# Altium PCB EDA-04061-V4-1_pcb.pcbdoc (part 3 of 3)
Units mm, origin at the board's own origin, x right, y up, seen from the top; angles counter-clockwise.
Board outline 105 x 56 mm, 6 copper layers (Top Layer, L2, L3, L4, L5, Bottom Layer), stack 1.58 mm thick; 213 components, 137 nets, 766 pads, 477 vias.

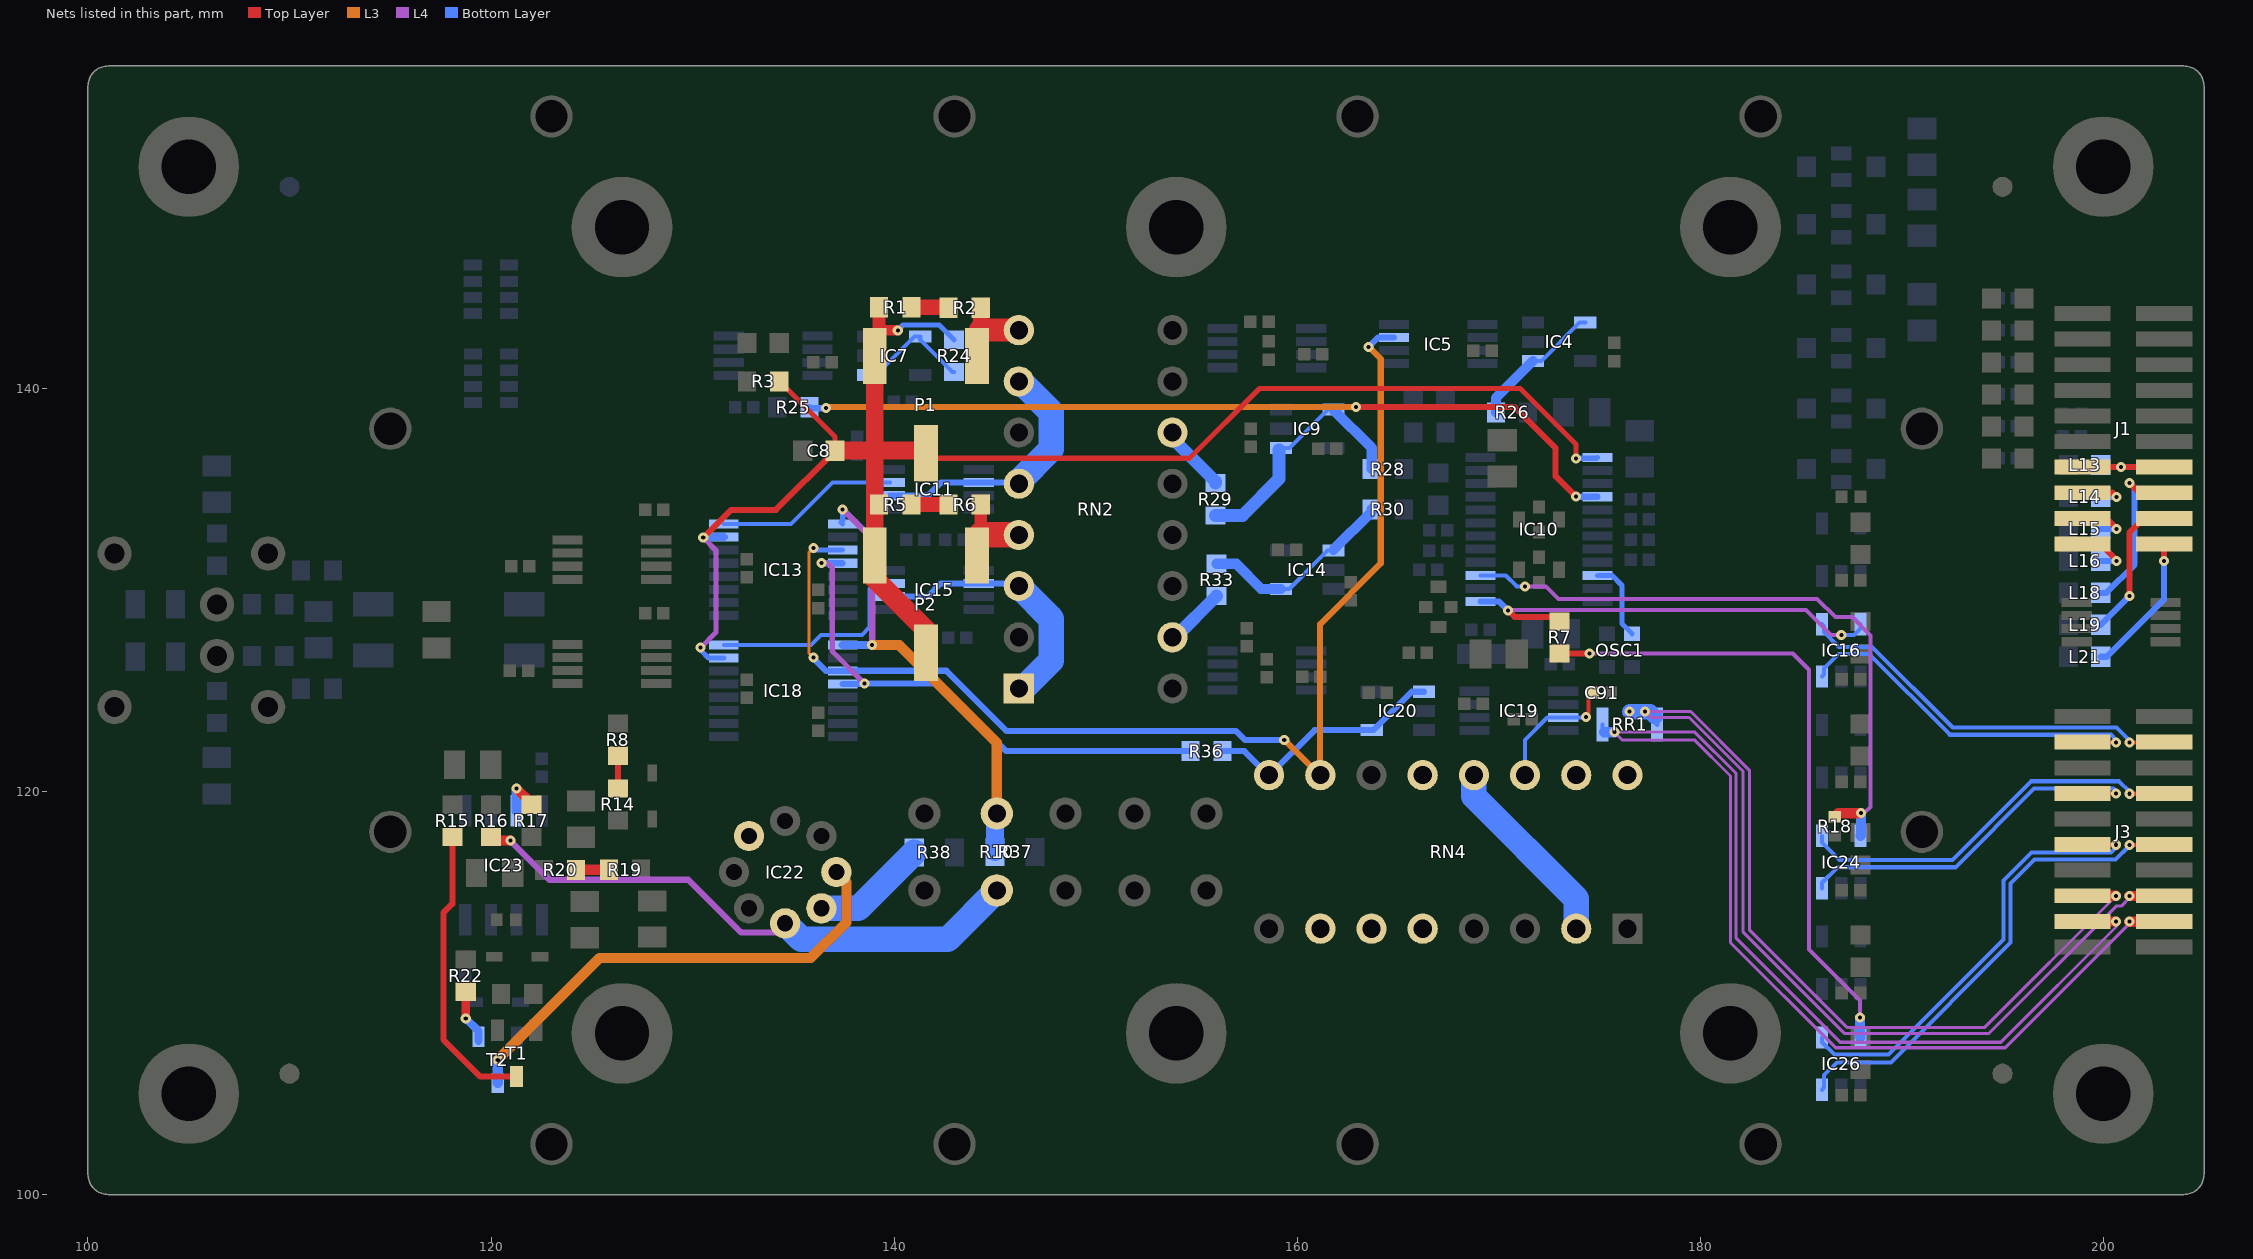
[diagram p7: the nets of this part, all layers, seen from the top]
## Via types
v1: diameter 0.5, hole 0.2, Top Layer to Bottom Layer, tented both sides, 477 vias

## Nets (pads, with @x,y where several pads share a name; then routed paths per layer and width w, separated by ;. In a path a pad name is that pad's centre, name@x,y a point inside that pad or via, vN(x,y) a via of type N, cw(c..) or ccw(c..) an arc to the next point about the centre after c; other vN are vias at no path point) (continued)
NetIC4_1: IC4.1 IC4.4 R26.1 | length 6.7
  Bottom Layer w0.203: IC4.1@171.7,141.363 172.122,141.363 174.022,143.263 IC4.4@174.3,143.263
  Bottom Layer w0.508: R26.1@169.863,138.808 169.863,139.526 IC4.1@171.7,141.363
NetIC7_1: IC7.1 IC7.4 R24.1 | length 5.9
  Bottom Layer w0.203: IC7.1@138.7,140.669 139.112,140.669 141.012,142.569 IC7.4@141.3,142.569 141.3,142.401 142.888,140.813 R24.1@142.977,140.813
NetIC9_1: IC9.1 IC9.4 R28.1 R29.2 | length 12.6
  Bottom Layer w0.203: IC9.1@159.2,137.05 159.623,137.05 161.523,138.95 IC9.4@161.8,138.95
  Bottom Layer w0.254: IC9.1@159.106,136.956 IC9.1@159.2,137.05
  Bottom Layer w0.508: IC9.4@161.8,138.95 163.7,137.05 R28.1@163.7,136
  Bottom Layer w0.635: R29.2@155.946,133.7 157.289,133.7 159.106,135.517 IC9.1@159.106,136.956
NetIC10_10: IC10.10 OSC1.3 | length 4
  Bottom Layer w0.254: IC10.10@174.9,130.725 175.62,130.725 176.124,130.221 176.124,128.326 OSC1.3@176.625,127.825
NetIC11_2: IC11.2 IC11.6 RN2.5 RN2.7 | length 13.1
  Bottom Layer w0.305: IC11.2@139.8,134.675 141.675,134.675 142.325,135.325 IC11.6@144.2,135.325 RN2.5@146.135,135.325
  Bottom Layer w1.27: RN2.5@146.19,135.27 146.135,135.325 147.803,136.993 147.803,138.819 146.272,140.35 RN2.7@146.19,140.35
NetIC11_3: IC11.3 IC13.8 | length 9.1
  Bottom Layer w0.203: IC13.8@131.547,133.276 134.894,133.276 136.943,135.325 IC11.3@139.8,135.325
NetIC14_1: IC14.1 IC14.4 R30.1 R33.2 | length 9.9
  Bottom Layer w0.203: IC14.4@159.2,130.05 159.608,130.05 161.508,131.95 IC14.1@161.8,131.95 IC14.1@161.8,131.988
  Bottom Layer w0.508: R33.2@156,131.3 156.973,131.3 158.223,130.05 IC14.4@159.2,130.05 ; IC14.1@161.8,131.988 163.7,133.888 R30.1@163.7,134
NetIC15_2: IC15.2 IC15.6 RN2.1 RN2.3 | length 13.3
  Bottom Layer w0.203: RN2.3@146.055,130.325 RN2.3@146.19,130.19
  Bottom Layer w0.305: IC15.2@139.8,129.675 141.675,129.675 142.325,130.325 IC15.6@144.2,130.325 RN2.3@146.055,130.325
  Bottom Layer w1.27: RN2.1@146.19,125.11 146.413,125.11 147.803,126.5 147.803,128.577 RN2.3@146.19,130.19
NetIC15_3: IC15.3 IC18.8 | length 10.6
  Bottom Layer w0.203: IC18.8@131.55,127.275 135.878,127.275 136.373,127.77 138.405,127.77 138.786,128.151 138.786,130.056 139.055,130.325 IC15.3@139.8,130.325
NetIC20_1: IC20.1 IC20.4 R36.1 RN4.9 | length 12.2
  Bottom Layer w0.305: R36.1@156.3,122 157.383,122 158.598,120.785 160.863,123.05 IC20.4@163.7,123.05 163.784,123.05 165.684,124.95 IC20.1@166.3,124.95
NetIC22_2: IC22.2 T2.3 | length 24
  L3 w0.508: v1(120.332,106.68) 125.395,111.743 135.871,111.743 137.643,113.515 137.643,115.492 IC22.2@137.135,116
  Bottom Layer w0.508: T2.3@120.332,105.53 v1(120.332,106.68)
NetIC22_3: IC22.3 R38.1 | length 5.8
  Bottom Layer w1.27: IC22.3@136.391,114.204 138.229,114.204 R38.1@141,116.975
NetIC22_4: IC22.4 R10.2 R16.1 | length 28.6
  Top Layer w0.508: R16.1@120,117.74 120.177,117.563 v1(120.956,117.563)
  L4 w0.152: IC22.4@134.135,113 IC22.4@134.595,113.46
  L4 w0.305: v1(120.956,117.563) 122.9,115.619 129.785,115.619 132.404,113 IC22.4@134.135,113
  Bottom Layer w1.27: IC22.4@134.595,113.46 135.388,112.667 142.67,112.667 R10.2@145.097,115.094 R10.2@145.097,115.05
NetIC23_3: IC23.3 R17.2 | length 2.2
  Top Layer w0.508: v1(121.26,120.15) 122,119.41 R17.2@122,119.34
  Bottom Layer w0.508: IC23.3@121.26,119.04 v1(121.26,120.15)
NetJ1_13: J1.13 J1.14 L13.1 | length 5.1
  Top Layer w0.305: J1.13@198.965,136.095 v1(200.889,136.095) J1.14@203.029,136.095
  Bottom Layer w0.305: L13.1@199.873,136.207 199.985,136.095 v1(200.889,136.095)
NetJ1_15: J1.15 L14.1 | length 2.6
  Top Layer w0.305: J1.15@198.965,134.825 200.455,134.825 v1(200.66,134.62)
  Bottom Layer w0.305: L14.1@199.873,134.62 v1(200.66,134.62)
NetJ1_16: J1.16 L18.1 | length 8.4
  Top Layer w0.305: v1(201.295,135.31) 201.78,134.825 J1.16@203.029,134.825
  Bottom Layer w0.305: L18.1@199.873,129.857 200.157,129.857 201.556,131.257 201.556,135.049 v1(201.295,135.31)
NetJ1_17: J1.17 L15.1 | length 2.7
  Top Layer w0.305: J1.17@198.965,133.555 200.137,133.555 v1(200.66,133.032)
  Bottom Layer w0.305: L15.1@199.873,133.032 v1(200.66,133.032)
NetJ1_18: J1.18 L19.1 | length 7.2
  Top Layer w0.305: v1(201.295,129.699) 201.295,132.846 202.004,133.555 J1.18@203.029,133.555
  Bottom Layer w0.305: L19.1@199.873,128.27 201.295,129.692 v1(201.295,129.699)
NetJ1_19: J1.19 L16.1 | length 2.9
  Top Layer w0.305: J1.19@198.965,132.285 199.86,132.285 200.66,131.485 v1(200.66,131.445)
  Bottom Layer w0.305: L16.1@199.873,131.445 v1(200.66,131.445)
NetJ1_20: J1.20 L21.1 | length 7.1
  Top Layer w0.305: v1(203.012,131.436) 203.012,132.268 J1.20@203.029,132.285
  Bottom Layer w0.305: L21.1@199.873,126.682 200.184,126.682 203.012,129.511 v1(203.012,131.436)
NetJ3_17: J3.17 J3.18 RR1.2 | length 82.6
  Top Layer w0.508: J3.17@198.965,113.555 198.974,113.546 v1(200.635,113.546) ; v1(201.295,113.538) 203.012,113.538 J3.18@203.029,113.555
  L4 w0.152: v1(200.635,113.546) 200.635,113.277 194.915,107.557 186.949,107.557 181.785,112.721 181.785,120.89 179.731,122.944 v1(175.743,122.944) 176.124,122.563 179.705,122.563 181.5,120.768 181.5,112.502 186.719,107.283 195.134,107.283 201.295,113.444 v1(201.295,113.538)
  Bottom Layer w0.203: RR1.2@175.155,123.325 175.155,123.024 RR1.2@175.235,122.944
  Bottom Layer w0.508: RR1.2@175.235,122.944 v1(175.743,122.944)
NetP1_1: P1.1 R2.2 RN2.8 | length 4.5
  Top Layer w0.762: P1.1@144.12,141.615 144.3,141.615 144.3,142.89 R2.2@144.3,144
  Top Layer w1.143: P1.1@144.3,142.89 RN2.8@146.19,142.89
NetP2_1: P2.1 R6.2 RN2.4 | length 4.5
  Top Layer w0.635: P2.1@144.12,131.709 144.12,132.55 144.3,132.73 R6.2@144.3,134.239
  Top Layer w1.27: P2.1@144.3,132.73 RN2.4@146.19,132.73
NetR1_2: R1.2 R2.1 | length 1.9
  Top Layer w0.762: R1.2@140.856,144.026 142.674,144.026 R2.1@142.7,144
NetR5_2: R5.2 R6.1 | length 1.8
  Top Layer w0.762: R5.2@140.856,134.239 R6.1@142.7,134.239
NetR8_1: R8.1 R14.2 | length 1.6
  Top Layer w0.305: R14.2@126.3,120.154 R8.1@126.3,121.775
NetR15_2: R15.2 T1.3 | length 14.6
  Top Layer w0.305: R15.2@118.087,117.74 118.087,114.432 117.637,113.983 117.637,107.687 119.474,105.85 T1.3@121.271,105.85
NetR19_2: R19.2 R20.1 | length 1.6
  Top Layer w0.508: R20.1@124.224,116.109 124.227,116.112 125.842,116.112 R19.2@125.845,116.115
NetR22_1: R22.1 T2.1 | length 2.9
  Top Layer w0.406: v1(118.745,108.744) R22.1@118.745,110.061
  Bottom Layer w0.406: v1(118.745,108.744) 119.38,108.109 119.38,107.632 119.382,107.635 T2.1@119.382,107.83
NetR29_1: R29.1 RN2.11 | length 3.4
  Bottom Layer w0.635: RN2.11@153.81,137.81 153.81,137.511 155.946,135.375 R29.1@155.946,135.3
NetR33_1: R33.1 RN2.15 | length 3
  Bottom Layer w0.635: RN2.15@153.81,127.65 153.95,127.65 R33.1@156,129.7
NetRN4_2: RN4.2 RN4.13 | length 9.7
  Bottom Layer w1.27: RN4.13@168.77,120.81 168.77,119.757 173.85,114.677 RN4.2@173.85,113.19
REF_5V: C91.2 IC5.3 IC13.11 IC18.11 IC19.3 RN4.10 RN4.12 RN4.14 RN4.15 RN4.16 | length 66
  Top Layer w0.203: v1(174.331,123.706) 174.331,123.786 174.45,123.905 174.45,124.692 C91.2@174.658,124.9 ; RN4.10@161.138,120.785 161.265,120.785 161.138,120.912 RN4.10@161.138,120.785
  L3 w0.152: v1(135.992,126.65) 135.77,126.872 135.77,131.844 v1(136.009,132.084)
  L3 w0.305: v1(159.36,122.563) 161.138,120.785 161.138,128.3 164.152,131.314 164.152,141.462 v1(163.551,142.063)
  Bottom Layer w0.203: RN4.14@171.31,120.81 171.298,120.822 171.298,122.563 172.41,123.675 IC19.3@173.2,123.675 174.3,123.675 v1(174.331,123.706)
  Bottom Layer w0.254: v1(136.009,132.084) 136.117,131.976 IC13.11@137.447,131.976
  Bottom Layer w0.305: v1(135.992,126.65) 135.992,126.611 136.628,125.975 IC18.11@137.45,125.975 137.467,125.992 142.596,125.992 145.59,122.998 156.973,122.998 157.408,122.563 v1(159.36,122.563) ; v1(163.551,142.063) 164.017,142.529 IC5.3@164.8,142.529
REF_10V: IC13.12 IC18.12 R36.2 | length 26.8
  L4 w0.254: v1(136.39,131.343) 136.704,131.343 136.93,131.117 136.93,126.959 v1(138.532,125.357)
  Bottom Layer w0.305: v1(136.39,131.343) 136.407,131.326 IC13.12@137.447,131.326 ; IC18.12@137.45,125.325 138.5,125.325 v1(138.532,125.357) 142.206,125.357 145.563,122 R36.2@154.7,122
REF_GND: IC13.9 IC18.9 IC22.7 R10.1 R37.2 RN4.5 RN4.6 RN4.7 | length 22.7
  L4 w0.305: v1(137.45,134) 138.913,132.537 v1(138.913,127.262)
  L3 w0.508: v1(138.913,127.262) 140.251,127.262 145.097,122.416 R10.1@145.097,119.451
  Bottom Layer w0.152: v1@138.773,127.275 138.9,127.275 v1(138.913,127.262)
  Bottom Layer w0.254: IC13.9@137.447,133.276 137.365,133.358 137.45,133.443 v1(137.45,134)
  Bottom Layer w0.406: IC18.9@137.45,127.275 v1@138.773,127.275
  Bottom Layer w0.889: R37.2@145,117 R10.1@145,118.904
SCK: IC10.13 IC16.5 R7.1 | length 22.7
  Top Layer w0.203: R7.1@172.975,128.443 R7.1@173.025,128.443
  Top Layer w0.305: v1(170.472,128.978) 170.79,128.659 172.759,128.659 R7.1@172.975,128.443
  L4 w0.203: v1(170.472,128.978) 170.497,129.003 185.254,129.003 186.496,127.762 v1(187,127.762)
  Bottom Layer w0.203: v1(187,127.762) 187.624,127.762 187.95,128.088 IC16.5@187.95,128.3
  Bottom Layer w0.305: IC10.13@169.1,129.425 170.024,129.425 v1(170.472,128.978)
SCK_DIFF_N: IC16.4 J3.4 | length 19.6
  Top Layer w0.203: v1(201.295,122.436) 203.02,122.436 J3.4@203.029,122.445
  Bottom Layer w0.203: IC16.4@186.05,128.3 186.152,128.198 186.152,127.902 186.498,127.556 186.498,127.554 186.792,127.26 186.794,127.26 186.876,127.178 188.527,127.178 192.532,123.173 200.66,123.173 201.295,122.538 v1(201.295,122.436)
SCK_DIFF_P: IC16.3 J3.3 | length 18.8
  Top Layer w0.203: J3.3@198.965,122.445 198.974,122.436 v1(200.635,122.436)
  Bottom Layer w0.203: IC16.3@186.05,125.7 186.152,125.802 186.152,126.114 186.86,126.822 188.38,126.822 192.385,122.817 200.381,122.817 200.635,122.563 v1(200.635,122.436)
SCK_FB: IC26.5 R7.2 | length 32
  Top Layer w0.305: R7.2@173.025,126.843 v1(174.5,126.843)
  L4 w0.203: v1(174.5,126.843) 184.593,126.843 185.395,126.041 185.395,112.161 187.933,109.623 v1(187.933,108.778)
  Bottom Layer w0.508: v1(187.933,108.778) 187.933,107.817 IC26.5@187.95,107.8
SCK_FB_DIFF_N: IC26.3 J3.12 | length 24.1
  Top Layer w0.203: v1(201.295,117.348) 203.012,117.348 J3.12@203.029,117.365
  Bottom Layer w0.203: IC26.3@186.05,105.2 186.152,105.302 186.152,105.921 186.792,106.561 189.459,106.561 195.403,112.505 195.403,115.431 196.591,116.619 200.608,116.619 201.295,117.307 v1(201.295,117.348)
SCK_FB_DIFF_P: IC26.4 J3.11 | length 22.9
  Top Layer w0.203: J3.11@198.965,117.365 198.974,117.356 v1(200.635,117.356)
  Bottom Layer w0.203: IC26.4@186.05,107.8 186.05,107.557 186.665,106.942 189.337,106.942 195.047,112.652 195.047,115.578 196.444,116.975 200.381,116.975 200.635,117.229 v1(200.635,117.356)
SYNC: IC10.15 IC24.5 R18.1 | length 32.2
  Top Layer w0.203: v1@187.959,118.923 v1(187.982,118.923)
  Top Layer w0.508: R18.1@186.665,118.74 186.848,118.923 v1@187.959,118.923
  L4 w0.203: v1(171.298,130.177) 172.349,130.177 172.972,129.554 185.8,129.554 186.705,128.65 187.544,128.65 188.452,127.742 188.452,119.239 188.136,118.923 v1(187.982,118.923)
  Bottom Layer w0.203: IC10.15@169.1,130.725 170.35,130.725 170.899,130.177 v1(171.298,130.177)
  Bottom Layer w0.508: IC24.5@187.95,117.8 187.982,117.832 v1(187.982,118.923)
SYNC_DIFF_N: IC24.4 J3.8 | length 19.6
  Top Layer w0.203: v1(201.295,119.888) 203.012,119.888 J3.8@203.029,119.905
  Bottom Layer w0.203: IC24.4@186.05,117.8 186.05,117.463 186.919,116.594 192.512,116.594 196.424,120.506 200.787,120.506 201.295,119.998 v1(201.295,119.888)
SYNC_DIFF_P: IC24.3 J3.7 | length 18.6
  Top Layer w0.203: J3.7@198.965,119.905 198.974,119.896 v1(200.635,119.896)
  Bottom Layer w0.203: IC24.3@186.05,115.2 186.05,115.471 186.817,116.238 192.659,116.238 196.571,120.15 200.508,120.15 200.635,120.023 v1(200.635,119.896)
TSensor: J3.15 J3.16 RR1.1 | length 80.6
  Top Layer w0.508: J3.15@198.965,114.825 200.626,114.825 v1(200.635,114.816) ; v1(201.295,114.808) 203.012,114.808 J3.16@203.029,114.825
  L4 w0.152: v1(177.267,123.96) 177.329,123.898 177.552,123.675 179.449,123.675 182.129,120.995 182.129,113.022 187.152,108 194.332,108 200.64,114.308 200.889,114.308 201.295,114.714 v1(201.295,114.808) ; v1(177.267,123.96) 179.541,123.96 182.441,121.06 182.441,113.14 187.299,108.282 194.101,108.282 v1(200.635,114.816)
  Bottom Layer w0.254: RR1.1@177.769,123.706 177.855,123.62 RR1.1@177.855,123.325
  Bottom Layer w0.762: v1(176.5,123.96) v1(177.267,123.96) ; v1(177.267,123.96) 177.515,123.96 RR1.1@177.769,123.706
VCM: C8.2 IC10.1 IC13.7 IC18.7 P1.2 P1.3 P2.2 P2.3 R1.1 R3.2 R5.1 R24.2 | length 85.4
  Top Layer w0.254: R3.2@134.3,140.35 134.317,140.35 135.021,139.646 137.071,137.596 C8.2@137.071,136.906 ; P1.2@141.58,136.785 141.832,136.533 154.665,136.533 158.132,140 171.073,140 173.838,137.235 v1(173.838,136.533)
  Top Layer w0.305: v1(130.531,132.596) 131.91,133.975 134.14,133.975 C8.2@137.071,136.906
  Top Layer w0.508: P1.3@139.256,142.883 v1(140.183,142.883)
  Top Layer w0.635: 139.04,136.912 139.04,136.914 ; P1.3@139.04,141.615 139.256,141.831 139.256,142.883 R1.1@139.256,144.026
  Top Layer w0.889: C8.2@137.071,136.906 137.079,136.914 139.04,136.914 P1.3@139.04,141.615 ; P2.3@139.04,131.709 R5.1@139.04,134.239 ; R5.1@139.256,134.239 R5.1@139.04,134.239 ; P1.2@141.58,136.785 141.453,136.912 139.04,136.912 R5.1@139.04,134.239
  Top Layer w1.016: P2.3@139.04,131.709 139.04,130.564 141.58,128.024 P2.2@141.58,126.879
  L4 w0.254: v1(130.404,127.135) 131.166,127.897 131.166,131.961 v1(130.531,132.596)
  Bottom Layer w0.254: v1(130.404,127.135) 130.404,127.008 130.787,126.625 IC18.7@131.55,126.625 ; v1(140.183,142.883) 140.448,143.148 142.242,143.148 R24.2@142.977,142.413 ; v1(173.838,136.533) 174.858,136.533 IC10.1@174.9,136.575
  Bottom Layer w0.406: v1(130.531,132.596) 130.561,132.626 IC13.7@131.547,132.626
VCM_REFOUT: IC10.4 R25.1 | length 41.8
  Top Layer w0.305: v1(162.916,139.073) 170.79,139.073 172.822,137.041 172.822,135.644 v1(173.838,134.628)
  L3 w0.305: v1(136.628,139.019) 136.682,139.073 v1(162.916,139.073)
  Bottom Layer w0.305: R25.1@135.801,139.065 135.847,139.019 v1(136.628,139.019) ; v1(173.838,134.628) 174.897,134.628 IC10.4@174.9,134.625
pads on no net: FTG1.FTG2 FTG2.FTG2 FTG3.FTG2 FTG4.FTG2 FTG5.FTG2 FTG6.FTG2 IC1.5 IC2.2 IC2.3 IC2.5 IC2.6 IC2.7 IC3.5 IC5.1 IC5.5 IC5.8 IC6.1 IC6.5 IC6.8 IC8.1 IC8.5 IC8.8 IC10.9 IC11.1 IC11.5 IC11.8 IC15.1 IC15.5 IC15.8 IC17.1 IC17.5 IC17.8 IC19.1 IC19.5 IC19.8 J3.13 RN1.4 RN1.5

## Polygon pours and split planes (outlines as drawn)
GND on Top Layer "GND_L01_P040" (solid, remove dead copper, pour order 40): 116.84,150.884 116.84,105.164 184.379,105.164 184.379,150.884 123.673,150.884
7V1 on Top Layer "7V1_L01_P018" (solid, remove dead copper, pour order 18): 139.882,121.123 139.882,115.823 165.982,115.823 167.488,114.317 167.488,112.123 177.182,112.123 177.182,118.923 158.682,118.923 156.482,121.123
GND on Top Layer "GND_L01_P030" (solid, remove dead copper, pour order 30): 186.03,154.409 186.03,101.792 204.826,101.792 204.826,154.409
REF_5V on Top Layer "REF_5V_L01_P020" (solid, remove dead copper, pour order 20): 177.5,122.2 160,122.2 160,119.6 177.5,119.6
no net on Panelisation "Panelisation" (hatched 45Degree grid 2.54 track 0.1): 339.8,226.8 82.6,226.8 82.6,239.8 cw(c84.6,239.8) 84.6,241.8 337.8,241.8 cw(c337.8,239.8) 339.8,239.8
no net on Panelisation "Panelisation" (hatched 45Degree grid 2.54 track 0.1): 339.8,97.6 82.6,97.6 82.6,84.6 ccw(c84.6,84.6) 84.6,82.6 337.8,82.6 ccw(c337.8,84.6) 339.8,84.6
GND on Bottom Layer "GND_L06_P066" (solid, remove dead copper, pour order 66): 185.903,155 113.5,155 113.5,133.975 100.178,133.975 100.178,122.089 113.5,122.089 113.5,104 116.5,104 116.5,152 185.903,152
GND on Bottom Layer "GND_L06_P068" (solid, remove dead copper, pour order 68): 113.5,151.011 113.5,105.037 184.506,105.037 184.506,151.011
GND on Bottom Layer "GND_L06_P064" (solid, remove dead copper, pour order 64): 192,155 204.826,155 204.826,101 113.5,101 113.5,104 185.776,104 185.776,155
GND on L2 "GND_L02_P058" (solid, remove dead copper, pour order 58): 100,100 100,156 205,156 205,100
REF_GND on L2 "REF_GND_L02_P056" (solid, remove dead copper, pour order 56): 167.615,111.641 167.615,115.832 166.218,117.229 159.811,117.229 155.44,121.6 134.267,121.6 130.912,118.245 130.912,114.054 133.325,111.641
TSensor on L5 "TSENSOR" (solid, pour order 60): 176.017,124.107 176.017,123.325 176.779,122.563 179.994,122.563 179.994,124.849 176.759,124.849
GND on L5 "GND_L05_P062" (solid, remove dead copper, pour order 62): 100,156 100,100 205,100 205,156
GND on L3 "GND_L03_P042" (solid, remove dead copper, pour order 42): 100,100 100,156 205,156 205,100
GND on L4 "GND_L04_P046" (solid, remove dead copper, pour order 46): 100,156 205,156 205,100 100,100

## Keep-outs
Keep-Out Layer:
  lines w0.2: 101,100 cw(c101,101) 100,101 100,155 cw(c101,155) 101,156 204,156 cw(c204,155) 205,155 205,101 ; 101,100 101,100 ; 101,100 204,100 ccw(c204,101) 205,101 ; 205,101 205,101
  lines w1: 125,100 130,100 ; 125,156 130,156 ; 175,100 180,100 ; 175,156 180,156

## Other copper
Top Layer:
  pour cut-out: 101.597,109.401 104.225,109.401 104.225,120.603 101.597,120.603
  text "TOP" at 113.114,111.733 h1.25 r90
  text "1" at 103.664,110.18 h1.27 r90
  text "EDA-04061-V4" at 111.114,107.733 h1.25 r90
  text ".Layer_Name" at 170.815,62.23 h1.91 r45
  text "1" at 169.862,57.15 h2.54
L4:
  pour cut-out: 101.597,109.401 104.225,109.401 104.225,120.603 101.597,120.603
  pour cut-out: 101.597,109.401 104.225,109.401 104.225,120.603 101.597,120.603
  text "4" at 103.656,116.242 h1.27 r90
  text ".Layer_Name" at 186.055,62.23 h1.91 r45
  text "4" at 184.468,57.15 h2.54
L5:
  pour cut-out: 101.597,109.401 104.225,109.401 104.225,120.603 101.597,120.603
  text "5" at 103.656,117.96 h1.27 r90
  text ".Layer_Name" at 192.722,63.817 h1.91 r45
  text "5" at 189.547,57.15 h2.54
L3:
  pour cut-out: 101.597,109.401 104.225,109.401 104.225,120.603 101.597,120.603
  text "3" at 103.656,113.557 h1.27 r90
  text ".Layer_Name" at 182.88,64.135 h1.91 r45
  text "3" at 179.387,57.15 h2.54
L2:
  pour cut-out: 101.597,109.401 104.225,109.401 104.225,120.603 101.597,120.603
  text "2" at 103.656,111.779 h1.27 r90
  text ".Layer_Name" at 175.895,62.23 h1.91 r45
  text "2" at 174.625,57.15 h2.54
Bottom Layer:
  pour cut-out: 101.597,109.401 104.225,109.401 104.225,120.603 101.597,120.603
  text "6" at 103.656,119.677 h1.27 r90
  text "BOT" at 111.735,111.571 h1.25 r270
  text "EDA-04061-V4" at 109.735,107.571 h1.25 r270
  text ".Layer_Name" at 208.28,74.295 h1.91 r45
  text "6" at 194.627,57.15 h2.54

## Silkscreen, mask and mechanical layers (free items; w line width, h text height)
Top Overlay:
  lines w0.2: 119.221,108.744 119.671,109.193 ; 123.19,114.776 123.349,114.935 123.349,115.252
  text "TOP" at 112.5,144 h1.25 r90
  text "EDA-04061-V4" at 110.5,139.5 h1.25 r90
  text "Licensed under CERN OHL-W v2.0" at 156.82,109.061 h0.91
  text "HPM7177 ADC Mezzanine V4" at 195.421,108.426 h1.3 r90
  text "http://ohwr.org/cernohl" at 160,107 h1
  text "https://www.ohwr.org/project/opt-adc-10k-32b-1cha/wikis" at 140.176,104.14 h1
  text ".Layer_Name" at 167.64,83.82 h1.91
Bottom Overlay:
  lines w0.2: 117.995,120.722 121.247,120.722 121.9,121.375 ; 163.036,122.055 169.43,122.055 169.579,122.204 ; 163.036,134.748 163.226,134.938 166.228,134.938 ; 165.338,132.159 165.894,132.715 ; 167,126.175 167.286,125.889 171.838,125.889 ; 167.472,128.586 167.633,128.746 169.901,128.746 170.07,128.577 170.79,128.577 ; 175.834,139.92 176.054,139.7 176.054,138.906 176.213,138.748 ; 177.8,135.096 178.156,135.452 178.156,139.073 ; 188.818,149.373 189.694,150.249 191.77,150.249 ; 189.484,145.987 189.865,146.368 191.77,146.368
  lines w0.254: 107.823,123.297 107.541,123.579 107.541,125.345 108.037,125.841 ; 107.823,132.727 107.541,132.445 107.541,130.679 108.037,130.183
  text "BOT" at 195.5,117 h1.5 r270
  text "EDA-04061-V4" at 198.12,108.902 h1.5 r270
  text ".Layer_Name" at 205.74,83.82 h1.91
Top Paste:
  text ".Layer_Name" at 167.64,78.74 h1.91
Bottom Paste:
  text ".Layer_Name" at 205.74,78.74 h1.91
Top Solder:
  region: 101.597,109.401 104.225,109.401 104.225,120.603 101.597,120.603
  text ".Layer_Name" at 167.64,81.28 h1.91
Bottom Solder:
  region: 101.597,109.401 104.225,109.401 104.225,120.603 101.597,120.603
  region: 123.8,150.63 123.8,105.291 184.125,105.291 184.125,150.63 179,150.63 179,110.5 129,110.5 129,145.5 179,145.5 179,150.63
  text ".Layer_Name" at 205.74,81.28 h1.91
Mechanical 1:
  the board outline again, w0.8
Mechanical 2:
  text "Components" at 130.81,83.82 h1.91
  text ".Component_Count" at 148.59,83.82 h1.91
  text "Pins" at 130.81,81.28 h1.91
  text ".Pad_Count" at 148.59,81.28 h1.91
  text "Vias" at 130.81,78.74 h1.91
  text ".Via_Count" at 148.59,78.74 h1.91
  text "Holes" at 130.81,76.2 h1.91
  text ".Hole_Count" at 148.59,76.2 h1.91
  text "Nets" at 130.81,73.66 h1.91
  text ".Net_Count" at 148.59,73.66 h1.91
Mechanical 4:
  lines w0.2: 72.6,82.6 82.6,82.6 82.6,72.6 ; 72.6,241.8 82.6,241.8 82.6,251.8 ; 80.1,90.1 80.1,80.1 90.1,80.1 ; 80.1,234.3 80.1,244.3 90.1,244.3 ; 97.6,102.6 97.6,97.6 102.6,97.6 ; 97.6,153.4 97.6,158.4 102.6,158.4 ; 97.6,171 97.6,166 102.6,166 ; 97.6,221.8 97.6,226.8 102.6,226.8 ; 100,105 100,100 105,100 ; 100,151 100,156 105,156 ; 100,173.4 100,168.4 105,168.4 ; 100,219.4 100,224.4 105,224.4 ; 200,100 205,100 205,105 ; 200,156 205,156 205,151 ; 200,168.4 205,168.4 205,173.4 ; 200,224.4 205,224.4 205,219.4 ; 202.4,97.6 207.4,97.6 207.4,102.6 ; 202.4,158.4 207.4,158.4 207.4,153.4 ; 202.4,166 207.4,166 207.4,171 ; 202.4,226.8 207.4,226.8 207.4,221.8 ; 215,102.6 215,97.6 220,97.6 ; 215,153.4 215,158.4 220,158.4 ; 215,171 215,166 220,166 ; 215,221.8 215,226.8 220,226.8 ; 217.4,105 217.4,100 222.4,100 ; 217.4,151 217.4,156 222.4,156 ; 217.4,173.4 217.4,168.4 222.4,168.4 ; 217.4,219.4 217.4,224.4 222.4,224.4 ; 317.4,100 322.4,100 322.4,105 ; 317.4,156 322.4,156 322.4,151 ; 317.4,168.4 322.4,168.4 322.4,173.4 ; 317.4,224.4 322.4,224.4 322.4,219.4 ; 319.8,97.6 324.8,97.6 324.8,102.6 ; 319.8,158.4 324.8,158.4 324.8,153.4 ; 319.8,166 324.8,166 324.8,171 ; 319.8,226.8 324.8,226.8 324.8,221.8 ; 332.3,80.1 342.3,80.1 342.3,90.1 ; 332.3,244.3 342.3,244.3 342.3,234.3 ; 339.8,72.6 339.8,82.6 349.8,82.6 ; 339.8,251.8 339.8,241.8 349.8,241.8
Corners:
  lines w0.2: 95,100 100,100 100,95 ; 95,156 100,156 100,161 ; 205,95 205,100 210,100 ; 205,161 205,156 210,156
  lines w0.254: 172.72,55.88 172.72,60.96 ; 177.8,55.88 177.8,60.96 ; 182.88,55.88 182.88,60.96 ; 187.96,55.88 187.96,60.96 ; 193.04,55.88 193.04,60.96 ; 167.64,55.88 167.64,60.96 198.12,60.96 198.12,55.88 167.64,55.88
Title Block:
  circle w0.305: c106.045,63.5 r3.81
  lines w0.254: 104.14,62.238 ccw(c108.585,62.23) 104.853,64.644 ; 113.03,62.23 113.03,66.675 ; 115.57,59.055 157.48,59.055 ; 115.57,62.23 157.48,62.23 ; 115.57,65.405 157.48,65.405 ; 129.54,55.88 129.54,68.58 ; 101.6,55.88 101.6,68.58 114.3,68.58 114.3,55.88 101.6,55.88 ; 115.57,55.88 115.57,68.58 157.48,68.58 157.48,55.88 115.57,55.88
  lines w0.305: 102.489,62.128 103.505,59.055 ; 105.537,56.007 108.61,60.681 ; 106.045,67.31 113.665,67.945 ; 109.779,64.262 112.395,55.88
  text "Number" at 116.84,66.04 h1.91
  text "EDA-04061-V4" at 130.81,66.04 h1.91
  text "Drawn By" at 116.84,62.865 h1.91
  text "N. Beev" at 130.81,62.865 h1.91
  text "CERN" at 102.87,62.611 h2.54
  text "DATE" at 116.84,59.69 h1.91
  text "04-04-2019" at 130.81,59.69 h1.91
  text "JM Combe (16/11/2021)" at 130.493,56.674 h1.52
  text "Checked" at 116.84,56.515 h1.91
  text "Print Date" at 116.84,53.34 h1.27
  text ".Print_Date" at 132.08,53.34 h1.27
  text ".Print_Time" at 144.78,53.34 h1.27
  text ".Print_Scale" at 116.84,51.435 h1.27
  text "Altium Designer Rev" at 116.84,49.53 h1.27
  text "'.Application_BuildNumber'" at 135.89,49.53 h1.27
Notvisible:
  circle w0.3: c101.062,141.49 r0.2
  circle w0.203: c113.995,144.975 r2.775
  lines w0: 98.546,149.86 99.054,149.86 ; 98.8,149.606 98.8,150.114
  lines w0.05: 101.063,140.19 116.938,147.81 ; 101.063,140.19 116.938,140.19 ; 101.063,140.19 101.063,147.81 ; 101.063,147.81 116.938,140.19 ; 101.063,147.81 116.938,147.81 ; 116.938,140.19 116.938,147.81
  lines w0.2: 97.6,149.61 97.6,150.11 ; 100,149.61 100,150.11 ; 107.705,142.845 107.705,143.845 ; 107.705,144.445 107.705,145.345
  lines w0.203: 101.063,141.49 101.063,140.19 108.683,140.19 108.683,143.845 ; 104.105,142.845 104.105,144.545 103.805,144.045 cw(c103.455,144.185) 103.105,144.045 102.805,144.545 102.805,142.845 cw(c102.455,142.795) 102.105,142.845 102.105,145.545 cw(c102.655,145.238) 103.205,145.545 103.455,145.045 103.705,145.545 cw(c104.255,145.178) 104.805,145.545 ; 104.105,142.845 ccw(c104.463,142.853) 104.805,142.745 ; 104.805,142.745 ccw(c105.372,143.124) 105.304,142.445 107.205,142.445 ccw(c107.205,142.957) 107.705,142.845 ; 104.805,145.545 cw(c105.305,145.278) 105.305,145.845 107.205,145.845 cw(c106.872,145.012) 107.705,145.345 ; 107.705,143.845 108.669,143.845 ; 107.705,144.445 108.683,144.445 108.683,147.75 113.996,147.75 ; 109.547,147.063 110.019,143.75 ; 110.1,140.495 111.294,145.606 ; 111.945,143.106 114.549,140.25 ; 114.747,146.081 ccw(c112.765,144.142) 115.525,143.873 ; 115.95,141.657 116.668,144.229 ; 104.804,143.045 cw(c105.324,142.471) 105.304,143.245 106.805,143.245 106.805,143.745 106.105,143.745 cw(c106.071,143.928) 105.905,143.845 104.805,143.845 104.805,143.045 ; 104.805,144.445 104.805,145.245 ccw(c105.305,145.77) 105.305,145.045 106.805,145.045 106.805,144.545 106.105,144.545 ccw(c106.071,144.362) 105.905,144.445 104.805,144.445
  lines w0.254: 167.64,62.23 198.12,62.23 ; 170.815,62.23 178.435,69.85 ; 175.895,62.23 183.515,69.85 ; 180.975,62.23 188.595,69.85 ; 186.055,62.23 193.675,69.85 ; 191.135,62.23 198.755,69.85 ; 196.215,62.23 207.327,73.343 ; 124,105.5 184,105.5 ; 124,105.5 124,150.5 ; 124,105.5 124,150.5 ; 124,105.5 184,105.5 ; 124,150.5 184,150.5 ; 124,150.5 184,150.5 ; 129,110.5 179,110.5 ; 129,110.5 129,145.5 ; 129,110.5 129,145.5 ; 129,110.5 179,110.5 ; 129,145.5 179,145.5 ; 129,145.5 179,145.5 ; 179,110.5 179,145.5 ; 179,110.5 179,145.5 ; 184,105.5 184,150.5 ; 184,105.5 184,150.5
  text "TE/MPE" at 107.413,146.54 h1
  text "CERN" at 116.112,144.381 h1.25
  text "NB/JMW" at 107.73,140.825 h1
Panelisation:
  pour cut-out: 175.386,241.8 175.386,234.3 247.014,234.3 247.014,241.8
  pour cut-out: 326.264,231.8 312.3,231.8 312.3,236.8 328.336,236.8 334.8,230.336 334.8,226.8 329.8,226.8 329.8,228.264
  pour cut-out: 323.764,92.6 312.3,92.6 312.3,87.6 325.836,87.6 335.836,97.6 328.764,97.6
  pour cut-out: 95.1,92.6 110.1,92.6 110.1,87.6 95.1,87.6
  lines w0.2: 82.6,90.1 95.1,90.1 ; 82.6,234.3 312.3,234.3 ; 97.6,82.6 97.6,87.6 ; 100.1,90.1 105.1,90.1 ; 107.6,82.6 107.6,87.6 ; 110.1,90.1 312.3,90.1 ; 127.5,97.6 127.5,100 ; 127.5,156 127.5,158.4 ; 127.5,166 127.5,168.4 ; 127.5,224.4 127.5,226.8 ; 177.5,97.6 177.5,100 ; 177.5,156 177.5,158.4 ; 177.5,166 177.5,168.4 ; 177.5,224.4 177.5,226.8 ; 244.9,97.6 244.9,100 ; 244.9,156 244.9,158.4 ; 244.9,166 244.9,168.4 ; 244.9,224.4 244.9,226.8 ; 294.9,97.6 294.9,100 ; 294.9,156 294.9,158.4 ; 294.9,166 294.9,168.4 ; 294.9,224.4 294.9,226.8 ; 314.8,82.6 314.8,87.6 ; 317.3,90.1 322.3,90.1 ; 319.3,234.3 327.3,234.3 332.3,229.3 332.3,206.3 ; 324.8,82.6 324.8,87.6 ; 327.982,93.282 332.3,97.6 332.3,102.6 ; 317.3,234.3 319.3,233.3 319.3,235.3 317.3,234.3 ; 326.568,91.868 327.275,93.989 328.689,92.575 326.568,91.868
  lines w0.254: 116.701,151.956 120.96,151.956 124.46,155.456 ; 124.46,155.456 123.96,153.956 122.96,154.956 124.46,155.456
  lines w0.5: 82.6,97.6 339.8,97.6 ; 82.6,226.8 339.8,226.8 ; 82.6,84.6 ccw(c84.6,84.6) 84.6,82.6 337.8,82.6 ccw(c337.8,84.6) 339.8,84.6 339.8,239.8 ccw(c337.8,239.8) 337.8,241.8 84.6,241.8 ccw(c84.6,239.8) 82.6,239.8 82.6,84.6
  text "Area without Copper & without Solder Mask on both Sides" at 177.488,237.608 h1.65
  text "OPTICAL TARGET" at 331.8,206.3 h2 r90
  text "Ø2mm not drilled" at 334.3,206.3 h2 r90
  text "Ø0.8" at 116.7,152.4 h2
  text "NOT PLATED HOLE" at 104.935,149.05 h2.54
  text "Dimensions are rounded to 0.1mm. Gerber data is the reference" at 338.744,130.802 h2.5 r90
  text "ALL DIMENSIONS ARE IN MILLIMETERS" at 335.744,128.718 h4 r90
  text "Ø3.5 ±0.05" at 331.8,103.6 h2 r90
  text "NOT PLATED HOLE" at 334.3,103.6 h2 r90
  text ".Layer_Name" at 167.64,66.04 h1.91
Panelisation2:
  lines w2.4: 124.5,98.8 101,98.8 cw(c101,101) 98.8,101 98.8,155 cw(c101,155) 101,157.2 124.5,157.2 ; 124.5,167.2 101,167.2 cw(c101,169.4) 98.8,169.4 98.8,223.4 cw(c101,223.4) 101,225.6 124.5,225.6 ; 130.5,98.8 174.5,98.8 ; 130.5,157.2 174.5,157.2 ; 130.5,167.2 174.5,167.2 ; 130.5,225.6 174.5,225.6 ; 180.5,98.8 204,98.8 ccw(c204,101) 206.2,101 206.2,155 ccw(c204,155) 204,157.2 180.5,157.2 ; 180.5,167.2 204,167.2 ccw(c204,169.4) 206.2,169.4 206.2,223.4 ccw(c204,223.4) 204,225.6 180.5,225.6 ; 241.9,98.8 218.4,98.8 cw(c218.4,101) 216.2,101 216.2,155 cw(c218.4,155) 218.4,157.2 241.9,157.2 ; 241.9,167.2 218.4,167.2 cw(c218.4,169.4) 216.2,169.4 216.2,223.4 cw(c218.4,223.4) 218.4,225.6 241.9,225.6 ; 247.9,98.8 291.9,98.8 ; 247.9,157.2 291.9,157.2 ; 247.9,167.2 291.9,167.2 ; 247.9,225.6 291.9,225.6 ; 297.9,98.8 321.4,98.8 ccw(c321.4,101) 323.6,101 323.6,155 ccw(c321.4,155) 321.4,157.2 297.9,157.2 ; 297.9,167.2 321.4,167.2 ccw(c321.4,169.4) 323.6,169.4 323.6,223.4 ccw(c321.4,223.4) 321.4,225.6 297.9,225.6
Drill Drawing:
  circle w0.25: c118.328,190.958 r0.833
  circle w0.25: c118.328,183.458 r0.5
  circle w0.25: c118.328,183.458 r0.833
  lines w0.25: 117.495,178.875 119.161,178.875 119.161,180.542 117.495,180.542 117.495,178.875 ; 117.495,186.375 119.161,186.375 119.161,188.042 117.495,188.042 117.495,186.375 ; 117.495,195.542 119.161,195.542 118.328,193.875 117.495,195.542 ; 117.495,197.625 118.328,198.042 119.161,197.625 118.745,198.458 119.161,199.292 118.328,198.875 117.495,199.292 117.911,198.458 117.495,197.625 ; 117.828,186.708 118.828,186.708 118.828,187.708 117.828,187.708 117.828,186.708 ; 117.828,195.208 118.828,195.208 118.328,194.208 117.828,195.208
  lines w0.5: 116,177.75 187.821,177.75 ; 116,200.25 187.821,200.25 ; 128.565,174 128.565,204 ; 140.977,174 140.977,204 ; 164.494,174 164.494,204 ; 174.417,174 174.417,204 ; 116,174 187.821,174 187.821,204 116,204 116,174
  text "Symbol" at 118.25,201.375 h1.8
  text "Count" at 129.69,201.375 h1.8
  text "Hole Size" at 142.102,201.375 h1.8
  text "Plated" at 165.619,201.375 h1.8
  text "Via/Pad" at 175.542,201.375 h1.8
  text "477" at 129.69,197.625 h1.5
  text "0.20mm (7.87mil)" at 142.102,197.625 h1.5
  text "PTH" at 165.619,197.625 h1.5
  text "Via" at 175.542,197.625 h1.5
  text "8" at 129.69,193.875 h1.5
  text "0.80mm (31.50mil)" at 142.102,193.875 h1.5
  text "PTH" at 165.619,193.875 h1.5
  text "Pad" at 175.542,193.875 h1.5
  text "42" at 129.69,190.125 h1.5
  text "0.90mm (35.43mil)" at 142.102,190.125 h1.5
  text "PTH" at 165.619,190.125 h1.5
  text "Pad" at 175.542,190.125 h1.5
  text "6" at 129.69,186.375 h1.5
  text "1.00mm (39.37mil)" at 142.102,186.375 h1.5
  text "PTH" at 165.619,186.375 h1.5
  text "Pad" at 175.542,186.375 h1.5
  text "12" at 129.69,182.625 h1.5
  text "1.60mm (62.99mil)" at 142.102,182.625 h1.5
  text "PTH" at 165.619,182.625 h1.5
  text "Pad" at 175.542,182.625 h1.5
  text "10" at 129.69,178.875 h1.5
  text "2.70mm (106.30mil)" at 142.102,178.875 h1.5
  text "PTH" at 165.619,178.875 h1.5
  text "Pad" at 175.542,178.875 h1.5
  text "555 Total" at 129.69,175.125 h1.5
  text "General tolerances +/-0.05mm unless otherwise stated" at 117,171 h1.5

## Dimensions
101,155 to 96.52,158.591 on Drill Drawing
337.8,239.8 to 342.3,241.55 on Panelisation
124.5,157.2 to 130.5,157.2 on Panelisation
97.6,150.11 to 100,150.11 on Panelisation
127.5,156 to 128.75,156 on Panelisation
82.6,82.6 to 82.6,90.1 on Panelisation
82.6,82.6 to 97.6,82.6 on Panelisation
339.8,239.8 to 314.8,234.3 on Panelisation
100,155 to 205,155 on Mechanical 2
205,100 to 205,156 on Mechanical 2
100,100 to 105,105 on Drill Drawing
100,100 to 105,105 on Drill Drawing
